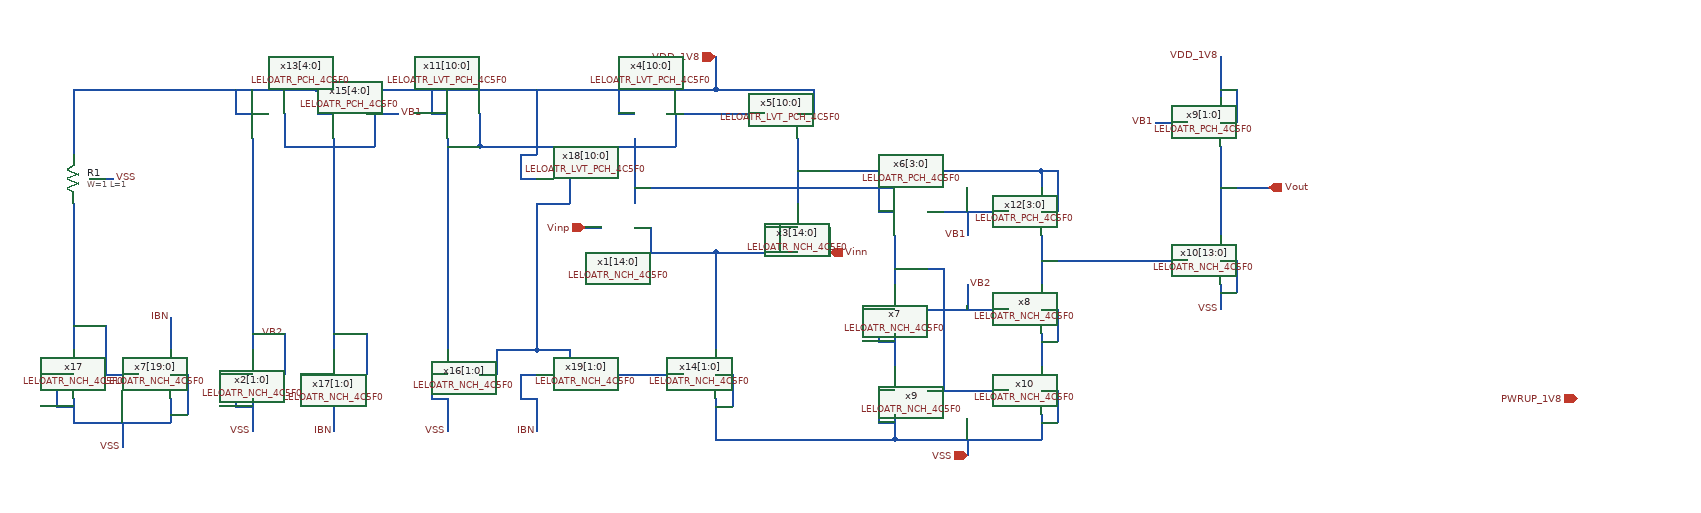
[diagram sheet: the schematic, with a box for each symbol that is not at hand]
v {xschem version=3.4.7 file_version=1.2}
G {}
K {}
V {}
S {}
E {}
P 4 1 -210 30 {}
N -260 -120 -160 -120 {lab=#net1}
N -360 -120 -260 -120 {lab=#net1}
N -260 -120 -260 -0 {lab=#net1}
N -360 -260 -360 -180 {lab=#net2}
N -320 -290 -200 -290 {lab=#net3}
N -360 -320 -260 -320 {lab=VDD_1V8}
N -260 -360 -260 -320 {lab=VDD_1V8}
N -260 -320 -160 -320 {lab=VDD_1V8}
N -180 -150 -160 -150 {lab=#net1}
N -180 -150 -180 -120 {lab=#net1}
N -360 -150 -340 -150 {lab=#net1}
N -340 -150 -340 -120 {lab=#net1}
N -380 -290 -360 -290 {lab=VDD_1V8}
N -470 -320 -360 -320 {lab=VDD_1V8}
N -360 -200 -40 -200 {lab=#net2}
N -160 -220 140 -220 {lab=#net4}
N 140 -220 140 -200 {lab=#net4}
N 0 -170 100 -170 {lab=VB1}
N -60 -170 -40 -170 {lab=#net2}
N -60 -200 -60 -170 {lab=#net2}
N 140 -170 160 -170 {lab=#net4}
N 160 -220 160 -170 {lab=#net4}
N 140 -220 160 -220 {lab=#net4}
N -40 -140 -40 -80 {lab=#net5}
N 140 -140 140 -80 {lab=#net6}
N -0 -50 100 -50 {lab=VB2}
N -40 -20 -40 20 {lab=#net7}
N 140 -20 140 20 {lab=#net8}
N 0 50 100 50 {lab=#net5}
N 140 80 140 110 {lab=VSS}
N -40 80 -40 110 {lab=VSS}
N -40 110 140 110 {lab=VSS}
N 50 110 50 130 {lab=VSS}
N -590 -260 -590 -200 {lab=#net3}
N -550 -290 -550 -250 {lab=#net3}
N -550 -250 -390 -250 {lab=#net3}
N -590 -320 -470 -320 {lab=VDD_1V8}
N 50 -80 50 -50 {lab=VB2}
N 50 -170 50 -140 {lab=VB1}
N -420 -150 -400 -150 {lab=Vinp}
N -120 -150 -120 -120 {lab=Vinn}
N -590 -250 -550 -250 {lab=#net3}
N -590 60 -590 100 {lab=VSS}
N -260 60 -260 100 {lab=VSS}
N -260 110 -40 110 {lab=VSS}
N -260 100 -260 110 {lab=VSS}
N -730 60 -730 100 {lab=IBN}
N -730 -260 -730 0 {lab=VB1}
N -690 -290 -650 -290 {lab=VB1}
N -730 -320 -590 -320 {lab=VDD_1V8}
N -750 30 -730 30 {lab=IBN}
N -750 30 -750 60 {lab=IBN}
N -750 60 -730 60 {lab=IBN}
N -750 -290 -730 -290 {lab=VDD_1V8}
N -750 -320 -750 -290 {lab=VDD_1V8}
N -750 -320 -730 -320 {lab=VDD_1V8}
N -680 -290 -680 -250 {lab=VB1}
N -730 -250 -680 -250 {lab=VB1}
N -610 30 -590 30 {lab=VSS}
N -610 30 -610 60 {lab=VSS}
N -610 60 -590 60 {lab=VSS}
N -610 -290 -590 -290 {lab=VDD_1V8}
N -610 -320 -610 -290 {lab=VDD_1V8}
N -60 -50 -40 -50 {lab=#net7}
N -60 -50 -60 -10 {lab=#net7}
N -60 -10 -40 -10 {lab=#net7}
N 140 -50 160 -50 {lab=#net8}
N 160 -50 160 -10 {lab=#net8}
N 140 -10 160 -10 {lab=#net8}
N 140 50 160 50 {lab=VSS}
N 160 50 160 90 {lab=VSS}
N 140 90 160 90 {lab=VSS}
N -60 50 -40 50 {lab=VSS}
N -60 50 -60 90 {lab=VSS}
N -60 90 -40 90 {lab=VSS}
N -260 30 -240 30 {lab=VSS}
N -240 30 -240 70 {lab=VSS}
N -260 70 -240 70 {lab=VSS}
N -1050 -170 -1050 0 {lab=#net9}
N -1050 -30 -1010 -30 {lab=#net9}
N -1010 -30 -1010 30 {lab=#net9}
N -1010 30 -970 30 {lab=#net9}
N -1050 60 -1050 90 {lab=VSS}
N -1050 90 -930 90 {lab=VSS}
N -930 60 -930 90 {lab=VSS}
N -990 90 -990 120 {lab=VSS}
N -1050 -320 -1050 -300 {lab=VDD_1V8}
N -1050 -320 -750 -320 {lab=VDD_1V8}
N -930 -40 -930 0 {lab=IBN}
N -1050 -300 -1050 -250 {lab=VDD_1V8}
N -930 30 -910 30 {lab=VSS}
N -910 30 -910 80 {lab=VSS}
N -930 80 -910 80 {lab=VSS}
N -1070 30 -1050 30 {lab=VSS}
N -1070 30 -1070 70 {lab=VSS}
N -1070 70 -1050 70 {lab=VSS}
N -1030 -210 -1000 -210 {lab=VSS}
N -850 -290 -830 -290 {lab=VDD_1V8}
N -850 -320 -850 -290 {lab=VDD_1V8}
N -830 -260 -830 0 {lab=VB2}
N -790 -20 -790 30 {lab=VB2}
N -830 -20 -790 -20 {lab=VB2}
N -830 60 -830 100 {lab=VSS}
N -850 30 -830 30 {lab=VSS}
N -850 30 -850 70 {lab=VSS}
N -850 70 -830 70 {lab=VSS}
N -160 -260 -160 -180 {lab=#net4}
N -160 -290 -140 -290 {lab=VDD_1V8}
N -140 -320 -140 -290 {lab=VDD_1V8}
N -160 -320 -140 -320 {lab=VDD_1V8}
N -360 -260 -360 -180 {lab=#net2}
N -550 30 -530 30 {lab=#net10}
N -390 -250 -310 -250 {lab=#net3}
N -310 -290 -310 -250 {lab=#net3}
N -380 -320 -380 -290 {lab=VDD_1V8}
N -440 -210 -440 -180 {lab=#net10}
N -480 -180 -440 -180 {lab=#net10}
N -480 -320 -480 -240 {lab=VDD_1V8}
N -440 30 -300 30 {lab=#net10}
N -440 0 -440 30 {lab=#net10}
N -480 -0 -440 -0 {lab=#net10}
N -480 -180 -480 -0 {lab=#net10}
N -480 60 -480 100 {lab=IBN}
N -500 30 -480 30 {lab=IBN}
N -500 30 -500 60 {lab=IBN}
N -500 60 -480 60 {lab=IBN}
N -500 -210 -480 -210 {lab=VDD_1V8}
N -500 -240 -500 -210 {lab=VDD_1V8}
N -500 -240 -480 -240 {lab=VDD_1V8}
N -690 -20 -690 30 {lab=VB1}
N -730 -20 -690 -20 {lab=VB1}
N -790 -250 -730 -250 {lab=VB1}
N -790 -290 -790 -250 {lab=VB1}
N -530 -0 -480 0 {lab=#net10}
N -530 -0 -530 30 {lab=#net10}
N -590 -200 -590 -0 {lab=#net3}
N 20 -100 20 50 {lab=#net5}
N -40 -100 20 -100 {lab=#net5}
N 360 -360 360 -310 {lab=VDD_1V8}
N 360 -280 380 -280 {lab=VDD_1V8}
N 380 -320 380 -290 {lab=VDD_1V8}
N 360 -320 380 -320 {lab=VDD_1V8}
N 380 -290 380 -280 {lab=VDD_1V8}
N 360 -80 360 -50 {lab=VSS}
N 290 -110 320 -110 {lab=#net6}
N 360 -70 380 -70 {lab=VSS}
N 360 -200 420 -200 {lab=Vout}
N 360 -250 360 -140 {lab=Vout}
N 360 -110 380 -110 {lab=VSS}
N 380 -110 380 -70 {lab=VSS}
N 140 -110 290 -110 {lab=#net6}
N 280 -280 320 -280 {lab=VB1}
N -1050 -180 -1050 -170 {lab=#net9}
N -1050 -250 -1050 -240 {lab=VDD_1V8}
C {devices/opin.sym} 420 -200 0 0 {name=p1 lab=Vout}
C {devices/ipin.sym} -420 -150 0 0 {name=p2 lab=Vinp}
C {devices/ipin.sym} -120 -120 0 1 {name=p3 lab=Vinn}
C {devices/ipin.sym} 50 130 0 0 {name=p4 lab=VSS}
C {devices/ipin.sym} -260 -360 0 0 {name=p5 lab=VDD_1V8}
C {devices/ipin.sym} 800 60 0 0 {name=p6 lab=PWRUP_1V8}
C {LELO_ATR_SKY130A/LELOATR_NCH_4C5F0.sym} -400 -150 0 0 {name=x1[14:0] }
C {LELO_ATR_SKY130A/LELOATR_NCH_4C5F0.sym} -120 -150 0 1 {name=x3[14:0] }
C {LELO_ATR_SKY130A/LELOATR_PCH_4C5F0.sym} 0 -170 0 1 {name=x6[3:0] }
C {LELO_ATR_SKY130A/LELOATR_PCH_4C5F0.sym} 100 -170 0 0 {name=x12[3:0] }
C {LELO_ATR_SKY130A/LELOATR_NCH_4C5F0.sym} 0 -50 0 1 {name=x7 }
C {LELO_ATR_SKY130A/LELOATR_NCH_4C5F0.sym} 100 -50 0 0 {name=x8 }
C {LELO_ATR_SKY130A/LELOATR_NCH_4C5F0.sym} 0 50 0 1 {name=x9 }
C {LELO_ATR_SKY130A/LELOATR_NCH_4C5F0.sym} 100 50 0 0 {name=x10 }
C {LELO_ATR_SKY130A/LELOATR_NCH_4C5F0.sym} -300 30 0 0 {name=x14[1:0] }
C {devices/lab_pin.sym} 50 -140 0 0 {name=p7 sig_type=std_logic lab=VB1}
C {devices/lab_pin.sym} 50 -80 0 1 {name=p8 sig_type=std_logic lab=VB2}
C {LELO_ATR_SKY130A/LELOATR_NCH_4C5F0.sym} -550 30 0 1 {name=x16[1:0] }
C {LELO_ATR_SKY130A/LELOATR_NCH_4C5F0.sym} -690 30 0 1 {name=x17[1:0] }
C {LELO_ATR_SKY130A/LELOATR_PCH_4C5F0.sym} -690 -290 0 1 {name=x15[4:0] }
C {devices/lab_pin.sym} -650 -290 0 1 {name=p11 sig_type=std_logic lab=VB1}
C {devices/lab_pin.sym} -790 -20 1 0 {name=p12 sig_type=std_logic lab=VB2}
C {LELO_ATR_SKY130A/LELOATR_NCH_4C5F0.sym} -1010 30 0 1 {name=x17 }
C {LELO_ATR_SKY130A/LELOATR_NCH_4C5F0.sym} -970 30 0 0 {name=x7[19:0] }
C {devices/lab_pin.sym} -990 120 0 0 {name=p14 sig_type=std_logic lab=VSS}
C {devices/lab_pin.sym} -930 -40 0 0 {name=p13 sig_type=std_logic lab=IBN}
C {devices/lab_pin.sym} -1000 -210 0 1 {name=p15 sig_type=std_logic lab=VSS}
C {LELO_ATR_SKY130A/LELOATR_PCH_4C5F0.sym} -790 -290 0 1 {name=x13[4:0] }
C {LELO_ATR_SKY130A/LELOATR_NCH_4C5F0.sym} -790 30 0 1 {name=x2[1:0] }
C {devices/lab_pin.sym} -830 100 0 0 {name=p16 sig_type=std_logic lab=VSS}
C {LELO_ATR_SKY130A/LELOATR_LVT_PCH_4C5F0.sym} -200 -290 0 0 {name=x5[10:0] }
C {LELO_ATR_SKY130A/LELOATR_LVT_PCH_4C5F0.sym} -320 -290 0 1 {name=x4[10:0] }
C {LELO_ATR_SKY130A/LELOATR_LVT_PCH_4C5F0.sym} -550 -290 0 1 {name=x11[10:0] }
C {LELO_ATR_SKY130A/LELOATR_LVT_PCH_4C5F0.sym} -440 -210 0 1 {name=x18[10:0] }
C {LELO_ATR_SKY130A/LELOATR_NCH_4C5F0.sym} -440 30 0 1 {name=x19[1:0] }
C {devices/lab_pin.sym} -480 100 0 0 {name=p17 sig_type=std_logic lab=IBN}
C {devices/lab_pin.sym} -730 100 0 0 {name=p10 sig_type=std_logic lab=IBN}
C {devices/lab_pin.sym} -590 100 0 0 {name=p9 sig_type=std_logic lab=VSS}
C {devices/lab_pin.sym} 360 -360 0 0 {name=p18 sig_type=std_logic lab=VDD_1V8}
C {devices/lab_pin.sym} 360 -50 0 0 {name=p19 sig_type=std_logic lab=VSS}
C {LELO_ATR_SKY130A/LELOATR_PCH_4C5F0.sym} 320 -280 0 0 {name=x9[1:0] }
C {LELO_ATR_SKY130A/LELOATR_NCH_4C5F0.sym} 320 -110 0 0 {name=x10[13:0] }
C {devices/lab_pin.sym} 280 -280 0 0 {name=p20 sig_type=std_logic lab=VB1}
C {sky130_fd_pr/res_high_po.sym} -1050 -210 0 1 {name=R1
W=1
L=1
model=res_high_po
spiceprefix=X
mult=1}
